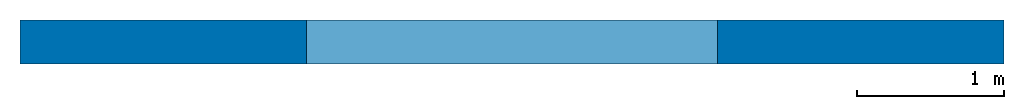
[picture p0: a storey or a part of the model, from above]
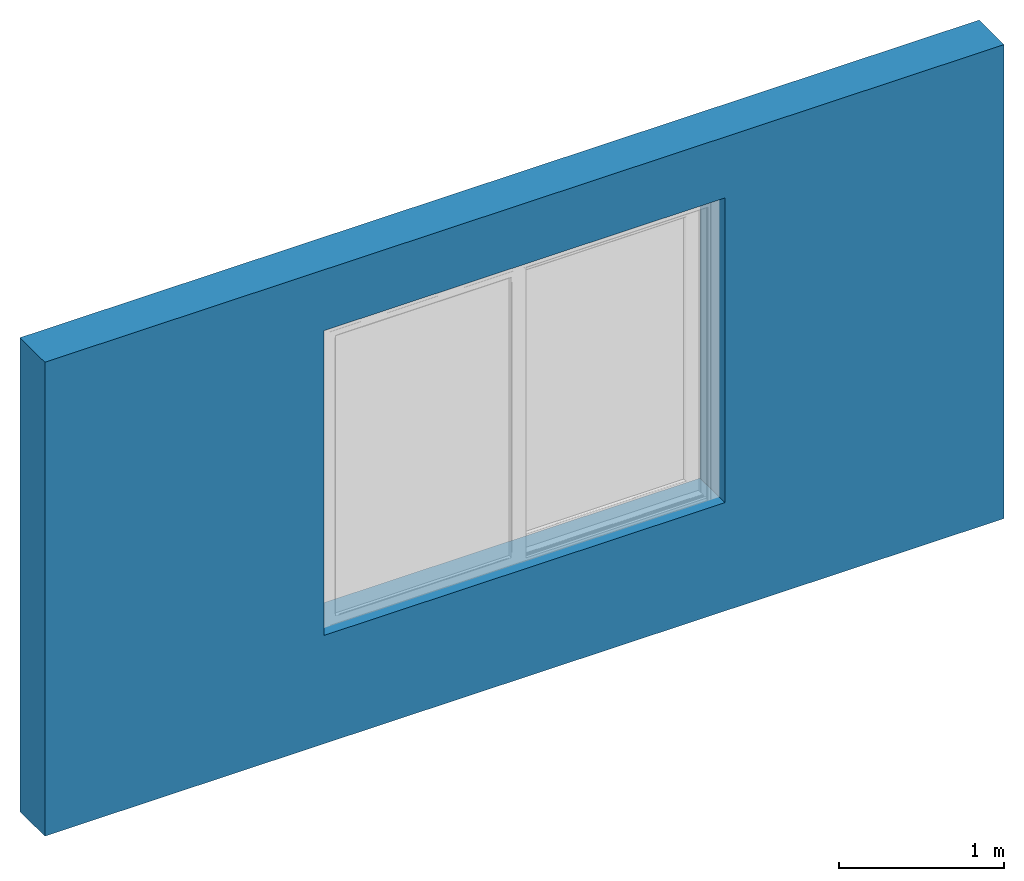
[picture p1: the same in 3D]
Properties of the parts of a building model (IFC2X3)

# File
Description: ViewDefinition [CoordinationView_V2.0]
File name: 0001
Time: 2020-12-01T13:00:29
Written by: The EXPRESS Data Manager Version 5.02.0100.07 : 28 Aug 2013
Made in: 20170223_1515(x64) - Exporter 18.0.0.420 - Alternate UI 18.0.0.420
Comment: STEP Physical File produced by: The EXPRESS Data Manager Version 5.02.0100.07 : 28 Aug 2013 * Module: EDMstepFileFactory/EDMstandAlone * Creation date: Tue Dec 01 13:00:29 2020 * Host: DESKTOP-49AJF0U * Database: C:\Users\SOCIAL~1\AppData\Local\Temp\{86C23D12-449D-414A-8B4F-41610E742FB8}\ifc * Database version: 5507 * Database creation date: Tue Dec 01 13:00:28 2020 * Schema: IFC2X3 * Model: DataRepository.ifc * Model creation date: Tue Dec 01 13:00:28 2020 * Header model: DataRepository.ifc_HeaderModel * Header model creation date: Tue Dec 01 13:00:28 2020 * EDMuser: sdai-user * EDMgroup: sdai-group * License ID and type: 5605 : Permanent license. Expiry date: * EDMstepFileFactory options: 020000

# IfcProject, 0001
LongName: Nome; Phase: Stato

# IfcSite, Default
RefLatitude: 41, 47, 59, 997253; RefLongitude: 12, 36, 0, 1373; RefElevation: 0 m

# IfcBuilding
Pset_BuildingCommon - NumberOfStoreys: 1

# IfcBuildingStorey, 0 - Piano Terra
LongName: 0 - Piano Terra; Elevation: 0 m

# IfcWallStandardCase: Muro di base:Generico - 30 cm, Muro di base:Generico - 30 cm:133289
In: 0 - Piano Terra
Type - PredefinedType: STANDARD; Material: Default - Muro 0.3 m
Pset_WallCommon - Reference: Generico - 30 cm; LoadBearing: no; ExtendToStructure: no; IsExternal: yes

# IfcWindow: HST Vision Minimal, HST Vision Minimal:HST Vision Minimal:147588
In: 0 - Piano Terra
Type - ParameterTakesPrecedence: no; Sizeable: no; Material: Alluminio, PVC, Vetro
OverallHeight: 2.25 m; OverallWidth: 2.8 m
Pset_WindowCommon - IsExternal: yes; Reference: HST Vision Minimal
Pset_ManufacturerTypeInformation - Manufacturer: Alphacan
